VERSION 5.7 ;
  NOWIREEXTENSIONATPIN ON ;
  DIVIDERCHAR "/" ;
  BUSBITCHARS "[]" ;
MACRO CCP_PMOS_58853955_X1_Y1_1653158392
  CLASS BLOCK ;
  FOREIGN CCP_PMOS_58853955_X1_Y1_1653158392 ;
  ORIGIN 0.000 0.000 ;
  SIZE 3.440 BY 11.160 ;
  OBS
      LAYER nwell ;
        RECT 0.000 0.000 3.440 7.560 ;
      LAYER li1 ;
        RECT 1.165 6.215 1.415 7.225 ;
        RECT 2.025 6.215 2.275 7.225 ;
        RECT 1.165 4.115 1.415 5.125 ;
        RECT 2.025 4.115 2.275 5.125 ;
        RECT 0.735 0.335 0.985 3.865 ;
        RECT 1.165 0.335 1.415 3.865 ;
        RECT 1.595 0.335 1.845 3.865 ;
        RECT 2.025 0.335 2.275 3.865 ;
        RECT 2.455 0.335 2.705 3.865 ;
      LAYER mcon ;
        RECT 1.205 6.635 1.375 6.805 ;
        RECT 2.065 6.635 2.235 6.805 ;
        RECT 1.205 4.955 1.375 5.125 ;
        RECT 2.065 4.535 2.235 4.705 ;
        RECT 0.775 1.175 0.945 1.345 ;
        RECT 1.205 0.335 1.375 0.505 ;
        RECT 1.635 1.175 1.805 1.345 ;
        RECT 2.065 0.755 2.235 0.925 ;
        RECT 2.495 1.175 2.665 1.345 ;
      LAYER met1 ;
        RECT 1.120 6.580 2.320 6.860 ;
        RECT 0.690 4.900 1.890 5.180 ;
        RECT 1.120 4.480 2.320 4.760 ;
        RECT 0.690 1.120 2.750 1.400 ;
        RECT 1.120 0.700 2.320 0.980 ;
        RECT 0.260 0.280 1.460 0.560 ;
      LAYER via ;
        RECT 2.020 6.590 2.280 6.850 ;
        RECT 1.590 4.910 1.850 5.170 ;
        RECT 1.160 4.490 1.420 4.750 ;
        RECT 2.020 1.130 2.280 1.390 ;
        RECT 1.590 0.710 1.850 0.970 ;
        RECT 1.160 0.290 1.420 0.550 ;
      LAYER met2 ;
        RECT 1.150 0.260 1.430 11.160 ;
        RECT 1.580 0.680 1.860 8.795 ;
        RECT 2.010 1.100 2.290 11.160 ;
  END
END CCP_PMOS_58853955_X1_Y1_1653158392
MACRO CMC_PMOS_23131506_X1_Y1_1653158394
  CLASS BLOCK ;
  FOREIGN CMC_PMOS_23131506_X1_Y1_1653158394 ;
  ORIGIN 0.000 0.000 ;
  SIZE 3.440 BY 7.560 ;
  OBS
      LAYER nwell ;
        RECT 0.000 0.000 3.440 7.560 ;
      LAYER li1 ;
        RECT 1.165 6.215 1.415 7.225 ;
        RECT 2.025 6.215 2.275 7.225 ;
        RECT 1.165 4.115 1.415 5.125 ;
        RECT 2.025 4.115 2.275 5.125 ;
        RECT 0.735 0.335 0.985 3.865 ;
        RECT 1.165 0.335 1.415 3.865 ;
        RECT 1.595 0.335 1.845 3.865 ;
        RECT 2.025 0.335 2.275 3.865 ;
        RECT 2.455 0.335 2.705 3.865 ;
      LAYER mcon ;
        RECT 1.205 6.635 1.375 6.805 ;
        RECT 2.065 6.635 2.235 6.805 ;
        RECT 1.205 4.535 1.375 4.705 ;
        RECT 2.065 4.535 2.235 4.705 ;
        RECT 0.775 1.175 0.945 1.345 ;
        RECT 1.205 0.335 1.375 0.505 ;
        RECT 1.635 1.175 1.805 1.345 ;
        RECT 2.065 0.755 2.235 0.925 ;
        RECT 2.495 1.175 2.665 1.345 ;
      LAYER met1 ;
        RECT 1.120 6.580 2.750 6.860 ;
        RECT 1.120 4.480 2.320 4.760 ;
        RECT 0.690 1.120 2.750 1.400 ;
        RECT 1.120 0.700 2.320 0.980 ;
        RECT 0.260 0.280 1.460 0.560 ;
      LAYER via ;
        RECT 2.450 6.590 2.710 6.850 ;
        RECT 2.450 1.130 2.710 1.390 ;
      LAYER met2 ;
        RECT 2.440 1.100 2.720 6.880 ;
  END
END CMC_PMOS_23131506_X1_Y1_1653158394
MACRO CCP_S_NMOS_B_5782581_X1_Y1_1653158393
  CLASS BLOCK ;
  FOREIGN CCP_S_NMOS_B_5782581_X1_Y1_1653158393 ;
  ORIGIN -0.605 -0.260 ;
  SIZE 9.170 BY 7.150 ;
  OBS
      LAYER pwell ;
        RECT 1.075 6.030 1.505 7.410 ;
        RECT 4.515 6.030 4.945 7.410 ;
        RECT 0.605 2.495 1.975 3.175 ;
        RECT 4.045 2.495 5.415 3.175 ;
      LAYER li1 ;
        RECT 1.165 6.215 1.415 7.225 ;
        RECT 4.605 6.215 4.855 7.225 ;
        RECT 1.165 4.115 1.415 5.125 ;
        RECT 4.605 4.115 4.855 5.125 ;
        RECT 0.735 0.335 0.985 3.865 ;
        RECT 1.165 0.335 1.415 3.865 ;
        RECT 1.595 0.335 1.845 3.865 ;
        RECT 4.175 0.335 4.425 3.865 ;
        RECT 4.605 0.335 4.855 3.865 ;
        RECT 5.035 0.335 5.285 3.865 ;
      LAYER mcon ;
        RECT 1.205 6.635 1.375 6.805 ;
        RECT 4.645 6.635 4.815 6.805 ;
        RECT 1.205 4.955 1.375 5.125 ;
        RECT 4.645 4.535 4.815 4.705 ;
        RECT 0.775 1.175 0.945 1.345 ;
        RECT 1.205 0.335 1.375 0.505 ;
        RECT 1.635 1.175 1.805 1.345 ;
        RECT 4.215 1.595 4.385 1.765 ;
        RECT 4.645 0.755 4.815 0.925 ;
        RECT 5.075 1.595 5.245 1.765 ;
      LAYER met1 ;
        RECT 1.120 6.580 9.775 6.860 ;
        RECT 1.120 4.900 3.610 5.180 ;
        RECT 2.840 4.480 4.900 4.760 ;
        RECT 4.130 1.540 5.330 1.820 ;
        RECT 0.690 1.120 1.890 1.400 ;
        RECT 3.270 0.700 4.900 0.980 ;
        RECT 1.120 0.280 3.180 0.560 ;
      LAYER via ;
        RECT 3.310 4.910 3.570 5.170 ;
        RECT 2.880 4.490 3.140 4.750 ;
        RECT 3.310 0.710 3.570 0.970 ;
        RECT 2.880 0.290 3.140 0.550 ;
      LAYER met2 ;
        RECT 2.870 0.260 3.150 4.780 ;
        RECT 3.300 0.680 3.580 5.200 ;
  END
END CCP_S_NMOS_B_5782581_X1_Y1_1653158393
MACRO DP_NMOS_B_93310865_X1_Y1_1653158395
  CLASS BLOCK ;
  FOREIGN DP_NMOS_B_93310865_X1_Y1_1653158395 ;
  ORIGIN -0.260 -0.280 ;
  SIZE 2.575 BY 7.130 ;
  OBS
      LAYER pwell ;
        RECT 1.075 6.030 2.365 7.410 ;
        RECT 0.605 2.495 2.835 3.175 ;
      LAYER li1 ;
        RECT 1.165 6.215 1.415 7.225 ;
        RECT 2.025 6.215 2.275 7.225 ;
        RECT 1.165 4.115 1.415 5.125 ;
        RECT 2.025 4.115 2.275 5.125 ;
        RECT 0.735 0.335 0.985 3.865 ;
        RECT 1.165 0.335 1.415 3.865 ;
        RECT 1.595 0.335 1.845 3.865 ;
        RECT 2.025 0.335 2.275 3.865 ;
        RECT 2.455 0.335 2.705 3.865 ;
      LAYER mcon ;
        RECT 1.205 6.635 1.375 6.805 ;
        RECT 2.065 6.635 2.235 6.805 ;
        RECT 1.205 4.535 1.375 4.705 ;
        RECT 2.065 4.955 2.235 5.125 ;
        RECT 0.775 1.175 0.945 1.345 ;
        RECT 1.205 0.335 1.375 0.505 ;
        RECT 1.635 1.175 1.805 1.345 ;
        RECT 2.065 0.755 2.235 0.925 ;
        RECT 2.495 1.175 2.665 1.345 ;
      LAYER met1 ;
        RECT 1.120 6.580 2.320 6.860 ;
        RECT 1.120 4.900 2.320 5.180 ;
        RECT 0.260 4.480 1.460 4.760 ;
        RECT 0.690 1.120 2.750 1.400 ;
        RECT 1.120 0.700 2.320 0.980 ;
        RECT 0.260 0.280 1.460 0.560 ;
  END
END DP_NMOS_B_93310865_X1_Y1_1653158395
MACRO NMOS_S_93862694_X1_Y1_1653158396
  CLASS BLOCK ;
  FOREIGN NMOS_S_93862694_X1_Y1_1653158396 ;
  ORIGIN -0.260 -0.280 ;
  SIZE 1.715 BY 7.130 ;
  OBS
      LAYER pwell ;
        RECT 1.075 6.030 1.505 7.410 ;
        RECT 0.605 2.285 1.975 3.385 ;
      LAYER li1 ;
        RECT 1.165 6.215 1.415 7.225 ;
        RECT 1.165 4.115 1.415 5.125 ;
        RECT 0.735 0.335 0.985 3.865 ;
        RECT 1.165 0.335 1.415 3.865 ;
        RECT 1.595 0.335 1.845 3.865 ;
      LAYER mcon ;
        RECT 1.205 6.635 1.375 6.805 ;
        RECT 1.205 4.535 1.375 4.705 ;
        RECT 0.775 0.755 0.945 0.925 ;
        RECT 1.205 0.335 1.375 0.505 ;
        RECT 1.635 0.755 1.805 0.925 ;
      LAYER met1 ;
        RECT 0.690 6.580 1.890 6.860 ;
        RECT 0.260 4.480 1.460 4.760 ;
        RECT 0.690 0.700 1.890 0.980 ;
        RECT 0.260 0.280 1.460 0.560 ;
      LAYER via ;
        RECT 1.590 6.590 1.850 6.850 ;
        RECT 1.590 0.710 1.850 0.970 ;
      LAYER met2 ;
        RECT 1.580 0.680 1.860 6.880 ;
  END
END NMOS_S_93862694_X1_Y1_1653158396
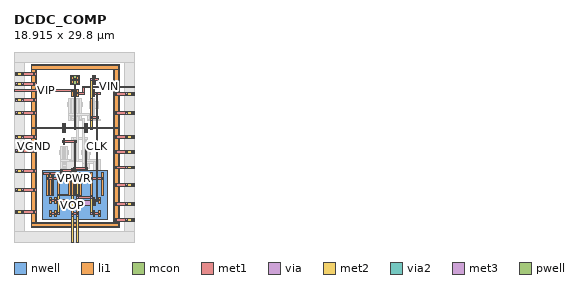
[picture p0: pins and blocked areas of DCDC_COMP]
MACRO DCDC_COMP
  CLASS BLOCK ;
  FOREIGN DCDC_COMP ;
  ORIGIN 0.000 0.000 ;
  SIZE 18.915 BY 29.800 ;
  PIN VPWR
    USE POWER ;
    PORT
      LAYER nwell ;
        RECT 4.405 3.600 14.725 11.160 ;
      LAYER li1 ;
        RECT 5.140 7.295 5.390 10.825 ;
        RECT 6.000 7.295 6.250 10.825 ;
        RECT 6.860 7.295 7.110 10.825 ;
        RECT 8.580 7.295 8.830 10.825 ;
        RECT 9.440 7.295 9.690 10.825 ;
        RECT 10.300 7.295 10.550 10.825 ;
        RECT 12.020 7.295 12.270 10.825 ;
        RECT 12.880 7.295 13.130 10.825 ;
        RECT 13.740 7.295 13.990 10.825 ;
        RECT 5.570 3.935 5.820 4.945 ;
        RECT 6.430 3.935 6.680 4.945 ;
        RECT 9.010 3.935 9.260 4.945 ;
        RECT 9.870 3.935 10.120 4.945 ;
        RECT 12.450 3.935 12.700 4.945 ;
        RECT 13.310 3.935 13.560 4.945 ;
      LAYER mcon ;
        RECT 5.180 9.815 5.350 9.985 ;
        RECT 6.040 9.815 6.210 9.985 ;
        RECT 6.900 9.815 7.070 9.985 ;
        RECT 8.620 9.815 8.790 9.985 ;
        RECT 9.480 9.815 9.650 9.985 ;
        RECT 10.340 9.815 10.510 9.985 ;
        RECT 12.060 9.815 12.230 9.985 ;
        RECT 12.920 9.815 13.090 9.985 ;
        RECT 13.780 9.815 13.950 9.985 ;
        RECT 5.610 4.355 5.780 4.525 ;
        RECT 6.470 4.355 6.640 4.525 ;
        RECT 9.050 4.355 9.220 4.525 ;
        RECT 9.910 4.355 10.080 4.525 ;
        RECT 12.490 4.355 12.660 4.525 ;
        RECT 13.350 4.355 13.520 4.525 ;
      LAYER met1 ;
        RECT 5.095 9.760 7.155 10.040 ;
        RECT 8.535 9.760 10.595 10.040 ;
        RECT 11.975 9.760 14.035 10.040 ;
        RECT 6.825 7.240 10.155 7.520 ;
        RECT 9.835 6.820 12.305 7.100 ;
        RECT 5.525 4.300 7.155 4.580 ;
        RECT 8.965 4.300 10.165 4.580 ;
        RECT 11.975 4.300 13.605 4.580 ;
      LAYER via ;
        RECT 6.855 9.770 7.115 10.030 ;
        RECT 9.865 9.770 10.125 10.030 ;
        RECT 12.015 9.770 12.275 10.030 ;
        RECT 6.855 7.250 7.115 7.510 ;
        RECT 9.865 7.250 10.125 7.510 ;
        RECT 9.865 6.830 10.125 7.090 ;
        RECT 12.015 6.830 12.275 7.090 ;
        RECT 6.855 4.310 7.115 4.570 ;
        RECT 9.865 4.310 10.125 4.570 ;
        RECT 12.015 4.310 12.275 4.570 ;
      LAYER met2 ;
        RECT 6.845 4.280 7.125 10.060 ;
        RECT 9.855 0.000 10.135 10.060 ;
        RECT 12.005 4.280 12.285 10.060 ;
    END
  END VPWR
  PIN VOP
    ANTENNAGATEAREA 0.252000 ;
    ANTENNADIFFAREA 0.352800 ;
    PORT
      LAYER li1 ;
        RECT 7.720 15.275 7.970 16.285 ;
        RECT 11.160 11.495 11.410 15.025 ;
        RECT 5.570 7.295 5.820 10.825 ;
        RECT 7.290 10.655 7.540 11.245 ;
        RECT 9.010 7.295 9.260 10.825 ;
        RECT 9.870 6.035 10.120 7.045 ;
      LAYER mcon ;
        RECT 7.760 15.695 7.930 15.865 ;
        RECT 11.200 11.495 11.370 11.665 ;
        RECT 7.330 11.075 7.500 11.245 ;
        RECT 5.610 10.655 5.780 10.825 ;
        RECT 7.330 10.655 7.500 10.825 ;
        RECT 9.050 10.655 9.220 10.825 ;
        RECT 9.910 6.455 10.080 6.625 ;
      LAYER met1 ;
        RECT 7.675 15.640 9.735 15.920 ;
        RECT 9.395 11.440 11.455 11.720 ;
        RECT 7.245 11.020 9.295 11.300 ;
        RECT 4.665 10.600 7.585 10.880 ;
        RECT 8.105 10.600 9.305 10.880 ;
        RECT 8.965 6.400 10.165 6.680 ;
      LAYER via ;
        RECT 9.435 15.650 9.695 15.910 ;
        RECT 9.435 11.450 9.695 11.710 ;
        RECT 9.005 11.030 9.265 11.290 ;
        RECT 9.005 10.610 9.265 10.870 ;
        RECT 9.005 6.410 9.265 6.670 ;
      LAYER met2 ;
        RECT 8.995 0.000 9.275 11.345 ;
        RECT 9.425 10.975 9.705 15.940 ;
      LAYER via2 ;
        RECT 8.995 11.020 9.275 11.300 ;
        RECT 9.425 11.020 9.705 11.300 ;
      LAYER met3 ;
        RECT 8.970 10.760 9.730 11.560 ;
    END
  END VOP
  PIN VIN
    ANTENNAGATEAREA 0.126000 ;
    PORT
      LAYER li1 ;
        RECT 9.870 22.835 10.120 23.845 ;
      LAYER mcon ;
        RECT 9.910 23.255 10.080 23.425 ;
      LAYER met1 ;
        RECT 10.745 24.175 18.915 24.455 ;
        RECT 10.745 23.480 11.025 24.175 ;
        RECT 9.825 23.200 11.025 23.480 ;
    END
  END VIN
  PIN VIP
    ANTENNAGATEAREA 0.126000 ;
    PORT
      LAYER li1 ;
        RECT 9.010 22.835 9.260 23.845 ;
      LAYER mcon ;
        RECT 9.050 23.675 9.220 23.845 ;
      LAYER met1 ;
        RECT 0.000 23.620 10.165 23.900 ;
    END
  END VIP
  PIN VGND
    USE GROUND ;
    PORT
      LAYER pwell ;
        RECT 2.670 26.990 16.470 27.850 ;
        RECT 2.670 3.090 3.530 26.990 ;
        RECT 8.920 24.750 10.210 26.130 ;
        RECT 12.360 24.750 12.790 26.130 ;
        RECT 7.630 17.190 8.060 18.570 ;
        RECT 11.070 17.190 11.500 18.570 ;
        RECT 15.610 3.090 16.470 26.990 ;
        RECT 2.670 2.230 16.470 3.090 ;
      LAYER li1 ;
        RECT 2.800 27.120 16.340 27.720 ;
        RECT 2.800 2.960 3.400 27.120 ;
        RECT 9.010 24.935 9.260 25.945 ;
        RECT 9.870 24.935 10.120 25.945 ;
        RECT 12.450 24.935 12.700 25.945 ;
        RECT 12.020 19.055 12.270 22.585 ;
        RECT 12.880 19.055 13.130 22.585 ;
        RECT 7.720 17.375 7.970 18.385 ;
        RECT 11.160 17.375 11.410 18.385 ;
        RECT 15.740 2.960 16.340 27.120 ;
        RECT 2.800 2.360 16.340 2.960 ;
      LAYER mcon ;
        RECT 3.010 26.255 3.180 26.425 ;
        RECT 9.050 25.355 9.220 25.525 ;
        RECT 9.910 25.355 10.080 25.525 ;
        RECT 12.490 25.355 12.660 25.525 ;
        RECT 3.010 24.745 3.180 24.915 ;
        RECT 15.960 23.155 16.130 23.325 ;
        RECT 3.010 22.145 3.180 22.315 ;
        RECT 3.010 20.175 3.180 20.345 ;
        RECT 12.060 19.475 12.230 19.645 ;
        RECT 12.920 19.475 13.090 19.645 ;
        RECT 15.960 20.090 16.130 20.260 ;
        RECT 3.010 17.800 3.180 17.970 ;
        RECT 7.760 17.795 7.930 17.965 ;
        RECT 11.200 17.795 11.370 17.965 ;
        RECT 15.960 17.785 16.130 17.955 ;
        RECT 3.010 16.340 3.180 16.510 ;
        RECT 3.010 14.215 3.180 14.385 ;
        RECT 3.010 11.085 3.180 11.255 ;
        RECT 3.010 8.110 3.180 8.280 ;
        RECT 3.010 4.610 3.180 4.780 ;
        RECT 15.960 16.360 16.130 16.530 ;
        RECT 15.960 14.020 16.130 14.190 ;
        RECT 15.960 11.610 16.130 11.780 ;
        RECT 15.960 8.885 16.130 9.055 ;
        RECT 15.960 5.955 16.130 6.125 ;
        RECT 15.960 3.420 16.130 3.590 ;
      LAYER met1 ;
        RECT 0.220 26.095 3.455 26.565 ;
        RECT 8.965 25.300 10.165 25.580 ;
        RECT 11.975 25.300 13.175 25.580 ;
        RECT 0.220 24.585 3.455 25.055 ;
        RECT 15.685 22.995 18.920 23.465 ;
        RECT 0.220 21.990 3.455 22.460 ;
        RECT 0.220 20.015 3.455 20.485 ;
        RECT 15.685 19.930 18.920 20.400 ;
        RECT 11.975 19.420 13.175 19.700 ;
        RECT 2.800 17.740 16.340 18.020 ;
        RECT 0.220 16.180 3.455 16.650 ;
        RECT 15.685 16.200 18.920 16.670 ;
        RECT 0.220 14.055 3.455 14.525 ;
        RECT 15.685 13.860 18.920 14.330 ;
        RECT 15.685 11.450 18.920 11.920 ;
        RECT 0.220 10.930 3.455 11.400 ;
        RECT 15.685 8.725 18.920 9.195 ;
        RECT 0.220 7.950 3.455 8.420 ;
        RECT 15.685 5.800 18.920 6.270 ;
        RECT 0.220 4.455 3.455 4.925 ;
        RECT 15.685 3.260 18.920 3.730 ;
      LAYER via ;
        RECT 0.310 26.210 0.570 26.470 ;
        RECT 1.155 26.210 1.415 26.470 ;
        RECT 9.435 25.310 9.695 25.570 ;
        RECT 12.015 25.310 12.275 25.570 ;
        RECT 0.310 24.700 0.570 24.960 ;
        RECT 1.155 24.700 1.415 24.960 ;
        RECT 17.530 23.110 17.790 23.370 ;
        RECT 18.375 23.110 18.635 23.370 ;
        RECT 0.310 22.105 0.570 22.365 ;
        RECT 1.155 22.105 1.415 22.365 ;
        RECT 0.310 20.130 0.570 20.390 ;
        RECT 1.155 20.130 1.415 20.390 ;
        RECT 17.530 20.045 17.790 20.305 ;
        RECT 18.375 20.045 18.635 20.305 ;
        RECT 12.015 19.430 12.275 19.690 ;
        RECT 9.435 17.750 9.695 18.010 ;
        RECT 12.015 17.750 12.275 18.010 ;
        RECT 0.310 16.295 0.570 16.555 ;
        RECT 1.155 16.295 1.415 16.555 ;
        RECT 17.530 16.315 17.790 16.575 ;
        RECT 18.375 16.315 18.635 16.575 ;
        RECT 0.310 14.170 0.570 14.430 ;
        RECT 1.155 14.170 1.415 14.430 ;
        RECT 17.530 13.975 17.790 14.235 ;
        RECT 18.375 13.975 18.635 14.235 ;
        RECT 17.530 11.565 17.790 11.825 ;
        RECT 18.375 11.565 18.635 11.825 ;
        RECT 0.310 11.045 0.570 11.305 ;
        RECT 1.155 11.045 1.415 11.305 ;
        RECT 17.530 8.840 17.790 9.100 ;
        RECT 18.375 8.840 18.635 9.100 ;
        RECT 0.310 8.065 0.570 8.325 ;
        RECT 1.155 8.065 1.415 8.325 ;
        RECT 17.530 5.915 17.790 6.175 ;
        RECT 18.375 5.915 18.635 6.175 ;
        RECT 0.310 4.570 0.570 4.830 ;
        RECT 1.155 4.570 1.415 4.830 ;
        RECT 17.530 3.375 17.790 3.635 ;
        RECT 18.375 3.375 18.635 3.635 ;
      LAYER met2 ;
        RECT 0.245 26.095 1.465 26.565 ;
        RECT 0.245 24.585 1.465 25.055 ;
        RECT 0.245 21.990 1.465 22.460 ;
        RECT 0.245 20.015 1.465 20.485 ;
        RECT 9.425 17.720 9.705 25.600 ;
        RECT 12.005 17.720 12.285 25.600 ;
        RECT 17.480 22.995 18.700 23.465 ;
        RECT 17.480 19.930 18.700 20.400 ;
        RECT 0.245 16.180 1.465 16.650 ;
        RECT 17.480 16.200 18.700 16.670 ;
        RECT 0.245 14.055 1.465 14.525 ;
        RECT 17.480 13.860 18.700 14.330 ;
        RECT 17.480 11.450 18.700 11.920 ;
        RECT 0.245 10.930 1.465 11.400 ;
        RECT 17.480 8.725 18.700 9.195 ;
        RECT 0.245 7.950 1.465 8.420 ;
        RECT 17.480 5.800 18.700 6.270 ;
        RECT 0.245 4.455 1.465 4.925 ;
        RECT 17.480 3.260 18.700 3.730 ;
    END
  END VGND
  PIN CLK
    ANTENNAGATEAREA 0.756000 ;
    PORT
      LAYER li1 ;
        RECT 12.450 22.835 12.700 23.845 ;
        RECT 5.570 6.035 5.820 7.045 ;
        RECT 6.430 6.035 6.680 7.045 ;
        RECT 12.450 6.035 12.700 7.045 ;
        RECT 13.310 6.035 13.560 7.045 ;
      LAYER mcon ;
        RECT 12.490 23.255 12.660 23.425 ;
        RECT 5.610 6.455 5.780 6.625 ;
        RECT 6.470 6.455 6.640 6.625 ;
        RECT 12.490 6.455 12.660 6.625 ;
        RECT 13.350 6.455 13.520 6.625 ;
      LAYER met1 ;
        RECT 12.405 23.200 13.605 23.480 ;
        RECT 5.525 6.400 8.435 6.680 ;
        RECT 12.405 6.400 13.605 6.680 ;
      LAYER via ;
        RECT 12.875 23.210 13.135 23.470 ;
        RECT 8.145 6.410 8.405 6.670 ;
        RECT 12.445 6.410 12.705 6.670 ;
        RECT 12.875 6.410 13.135 6.670 ;
      LAYER met2 ;
        RECT 8.135 5.935 8.415 6.700 ;
        RECT 12.435 5.935 12.715 6.700 ;
        RECT 12.865 6.380 13.145 23.500 ;
      LAYER via2 ;
        RECT 8.135 5.980 8.415 6.260 ;
        RECT 12.435 5.980 12.715 6.260 ;
      LAYER met3 ;
        RECT 8.110 5.720 12.740 6.520 ;
    END
  END CLK
  OBS
      LAYER pwell ;
        RECT 8.450 21.215 10.680 21.895 ;
        RECT 11.890 21.005 13.260 22.105 ;
        RECT 7.160 13.655 8.530 14.335 ;
        RECT 10.600 13.655 11.970 14.335 ;
      LAYER li1 ;
        RECT 8.580 19.055 8.830 22.585 ;
        RECT 9.010 19.055 9.260 22.585 ;
        RECT 9.440 19.055 9.690 22.585 ;
        RECT 9.870 19.055 10.120 22.585 ;
        RECT 10.300 19.055 10.550 22.585 ;
        RECT 11.590 19.055 11.840 20.065 ;
        RECT 12.450 19.055 12.700 22.585 ;
        RECT 11.160 15.275 11.410 16.285 ;
        RECT 7.290 11.495 7.540 15.025 ;
        RECT 7.720 11.495 7.970 15.025 ;
        RECT 8.150 11.495 8.400 15.025 ;
        RECT 10.730 11.495 10.980 15.025 ;
        RECT 11.590 11.495 11.840 15.025 ;
        RECT 6.430 7.295 6.680 10.825 ;
        RECT 9.870 7.295 10.120 10.825 ;
        RECT 12.450 7.295 12.700 10.825 ;
        RECT 13.310 7.295 13.560 10.825 ;
        RECT 9.010 6.035 9.260 7.045 ;
      LAYER mcon ;
        RECT 8.620 19.895 8.790 20.065 ;
        RECT 9.050 19.475 9.220 19.645 ;
        RECT 9.480 19.895 9.650 20.065 ;
        RECT 9.910 19.055 10.080 19.225 ;
        RECT 10.340 19.895 10.510 20.065 ;
        RECT 11.630 19.895 11.800 20.065 ;
        RECT 11.630 19.055 11.800 19.225 ;
        RECT 12.490 19.055 12.660 19.225 ;
        RECT 11.200 16.115 11.370 16.285 ;
        RECT 7.330 12.755 7.500 12.925 ;
        RECT 7.760 11.915 7.930 12.085 ;
        RECT 8.190 12.755 8.360 12.925 ;
        RECT 10.770 12.335 10.940 12.505 ;
        RECT 11.630 12.335 11.800 12.505 ;
        RECT 6.470 10.235 6.640 10.405 ;
        RECT 9.910 10.235 10.080 10.405 ;
        RECT 12.490 10.235 12.660 10.405 ;
        RECT 13.350 10.655 13.520 10.825 ;
        RECT 9.050 6.035 9.220 6.205 ;
      LAYER met1 ;
        RECT 8.535 19.840 11.885 20.120 ;
        RECT 8.965 19.420 10.165 19.700 ;
        RECT 9.825 19.000 11.025 19.280 ;
        RECT 11.545 19.000 13.605 19.280 ;
        RECT 8.965 16.060 11.455 16.340 ;
        RECT 7.245 12.700 13.595 12.980 ;
        RECT 10.685 12.280 12.735 12.560 ;
        RECT 7.675 11.860 9.305 12.140 ;
        RECT 13.265 10.600 14.465 10.880 ;
        RECT 5.525 10.180 8.435 10.460 ;
        RECT 8.965 10.180 10.165 10.460 ;
        RECT 12.405 10.180 13.605 10.460 ;
        RECT 8.535 5.980 9.735 6.260 ;
      LAYER via ;
        RECT 9.865 19.430 10.125 19.690 ;
        RECT 10.725 19.010 10.985 19.270 ;
        RECT 9.005 16.070 9.265 16.330 ;
        RECT 9.865 12.710 10.125 12.970 ;
        RECT 13.305 12.710 13.565 12.970 ;
        RECT 10.725 12.290 10.985 12.550 ;
        RECT 12.445 12.290 12.705 12.550 ;
        RECT 9.005 11.870 9.265 12.130 ;
        RECT 13.305 10.610 13.565 10.870 ;
        RECT 8.145 10.190 8.405 10.450 ;
        RECT 9.435 10.190 9.695 10.450 ;
        RECT 12.445 10.190 12.705 10.450 ;
        RECT 9.435 5.990 9.695 6.250 ;
      LAYER met2 ;
        RECT 8.995 11.840 9.275 16.360 ;
        RECT 9.855 12.680 10.135 19.720 ;
        RECT 10.715 12.260 10.995 19.300 ;
        RECT 8.135 9.715 8.415 10.480 ;
        RECT 9.425 2.365 9.705 10.480 ;
        RECT 12.435 10.160 12.715 12.580 ;
        RECT 13.295 10.580 13.575 13.000 ;
      LAYER via2 ;
        RECT 8.995 12.280 9.275 12.560 ;
        RECT 8.135 9.760 8.415 10.040 ;
        RECT 9.425 9.760 9.705 10.040 ;
      LAYER met3 ;
        RECT 0.245 26.095 1.465 26.565 ;
        RECT 0.245 24.585 1.465 25.055 ;
        RECT 17.480 22.995 18.700 23.465 ;
        RECT 0.245 21.990 1.465 22.460 ;
        RECT 0.245 20.015 1.465 20.485 ;
        RECT 17.480 19.930 18.700 20.400 ;
        RECT 0.245 16.180 1.465 16.650 ;
        RECT 17.480 16.200 18.700 16.670 ;
        RECT 0.245 14.055 1.465 14.525 ;
        RECT 17.480 13.860 18.700 14.330 ;
        RECT 8.680 12.020 9.300 12.820 ;
        RECT 17.480 11.450 18.700 11.920 ;
        RECT 0.245 10.930 1.465 11.400 ;
        RECT 8.110 9.500 9.730 10.300 ;
        RECT 17.480 8.725 18.700 9.195 ;
        RECT 0.245 7.950 1.465 8.420 ;
        RECT 17.480 5.800 18.700 6.270 ;
        RECT 0.245 4.455 1.465 4.925 ;
        RECT 17.480 3.260 18.700 3.730 ;
      LAYER via3 ;
        RECT 0.395 26.175 0.715 26.495 ;
        RECT 1.040 26.175 1.360 26.495 ;
        RECT 0.395 24.670 0.715 24.990 ;
        RECT 1.040 24.670 1.360 24.990 ;
        RECT 17.585 23.075 17.905 23.395 ;
        RECT 18.230 23.075 18.550 23.395 ;
        RECT 0.395 22.070 0.715 22.390 ;
        RECT 1.040 22.070 1.360 22.390 ;
        RECT 0.395 20.100 0.715 20.420 ;
        RECT 1.040 20.100 1.360 20.420 ;
        RECT 17.585 20.010 17.905 20.330 ;
        RECT 18.230 20.010 18.550 20.330 ;
        RECT 0.395 16.265 0.715 16.585 ;
        RECT 1.040 16.265 1.360 16.585 ;
        RECT 17.585 16.280 17.905 16.600 ;
        RECT 18.230 16.280 18.550 16.600 ;
        RECT 0.395 14.140 0.715 14.460 ;
        RECT 1.040 14.140 1.360 14.460 ;
        RECT 17.585 13.940 17.905 14.260 ;
        RECT 18.230 13.940 18.550 14.260 ;
        RECT 8.685 12.260 9.005 12.580 ;
        RECT 17.585 11.530 17.905 11.850 ;
        RECT 18.230 11.530 18.550 11.850 ;
        RECT 0.395 11.010 0.715 11.330 ;
        RECT 1.040 11.010 1.360 11.330 ;
        RECT 8.685 9.740 9.005 10.060 ;
        RECT 17.585 8.805 17.905 9.125 ;
        RECT 18.230 8.805 18.550 9.125 ;
        RECT 0.395 8.035 0.715 8.355 ;
        RECT 1.040 8.035 1.360 8.355 ;
        RECT 17.585 5.880 17.905 6.200 ;
        RECT 18.230 5.880 18.550 6.200 ;
        RECT 0.395 4.535 0.715 4.855 ;
        RECT 1.040 4.535 1.360 4.855 ;
        RECT 17.585 3.345 17.905 3.665 ;
        RECT 18.230 3.345 18.550 3.665 ;
      LAYER met4 ;
        RECT 0.000 0.000 1.600 29.800 ;
        RECT 8.255 9.735 9.435 12.585 ;
        RECT 17.315 0.000 18.915 29.800 ;
      LAYER via4 ;
        RECT 0.185 28.460 1.365 29.640 ;
        RECT 17.550 28.460 18.730 29.640 ;
        RECT 0.185 0.260 1.365 1.440 ;
        RECT 17.550 0.260 18.730 1.440 ;
      LAYER met5 ;
        RECT 0.000 28.200 18.915 29.800 ;
        RECT 0.000 0.000 18.915 1.600 ;
  END
END DCDC_COMP
END LIBRARY
